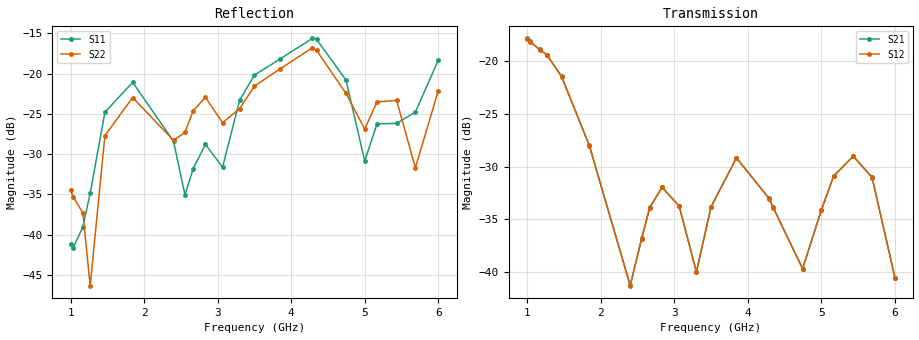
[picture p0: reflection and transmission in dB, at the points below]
!Agilent Technologies,E8364B,MY43040528,A.07.50.67
!Agilent E8364B: A.07.50.67
!Date: Sunday, March 01, 2026 21:28:26
!Correction: S11(Full 2 Port(1,2))
!S21(Full 2 Port(1,2))
!S12(Full 2 Port(1,2))
!S22(Full 2 Port(1,2))
!S2P File: Measurements: S11, S21, S12, S22:
# Hz S  dB  R 50
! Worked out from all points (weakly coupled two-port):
!   451 points, 1 GHz to 6 GHz, reference 50 ohm
!   highest |S21| = -17.90 dB at 1 GHz (marker M1); lowest = -41.2 dB at 2.4 GHz (marker M2)
!   lowest |S11| = -41.7 dB at 1.033 GHz (marker M3), VSWR 1.02, Z = 49.9 + j0.809 ohm
!   |S11| at or under -10 dB: start of sweep to end of sweep
!   |S22| runs from -46.3 to -16.7 dB; largest |S21 - S12| = 0.00049
!   S11 on the Smith chart (normalised r, x): 1 GHz: 1.00, +0.02; 4.289 GHz: 1.25, -0.28; 6 GHz: 0.98, -0.24
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1e9  -41.15 78.0  -17.90 25.8  -17.94 25.8  -34.42 14.5
1.033333e9  -41.71 99.3  -18.16 15.9  -18.20 15.9  -35.28 15.4
1.166667e9  -39.04 139.5  -18.93 -24.2  -18.96 -24.2  -37.28 15.5
1.266667e9  -34.86 170.4  -19.44 -56.7  -19.47 -56.7  -46.34 67.7
1.466667e9  -24.79 155.2  -21.49 -125.0  -21.51 -125.0  -27.70 86.2
1.844444e9  -21.07 87.2  -28.01 114.5  -28.04 114.5  -22.96 -1.4
2.4e9  -28.40 15.2  -41.22 -129.7  -41.25 -129.7  -28.28 -63.2
2.555556e9  -35.07 39.8  -36.78 117.8  -36.82 117.8  -27.29 -50.3
2.666667e9  -31.81 69.5  -33.84 62.1  -33.87 62.2  -24.61 -57.5
2.833333e9  -28.78 56.5  -31.94 -10.3  -31.97 -10.2  -22.93 -86.5
3.066667e9  -31.62 70.2  -33.74 -100.3  -33.77 -100.3  -26.10 -114.1
3.3e9  -23.26 79.1  -39.93 -136.5  -39.97 -136.5  -24.33 -100.2
3.5e9  -20.18 50.5  -33.78 -159.6  -33.82 -159.5  -21.54 -124.1
3.844444e9  -18.19 18.9  -29.17 73.7  -29.20 73.7  -19.43 -155.4
4.288889e9  -15.61 -41.8  -33.00 -91.7  -33.04 -91.6  -16.77 125.0
4.344444e9  -15.72 -50.4  -33.85 -111.7  -33.89 -111.7  -17.09 113.9
4.744444e9  -20.78 -110.1  -39.63 56.3  -39.67 56.3  -22.44 38.0
5e9  -30.86 -94.3  -34.08 -95.3  -34.11 -95.3  -26.87 39.2
5.166667e9  -26.22 -66.4  -30.88 -174.0  -30.92 -173.9  -23.50 27.9
5.433333e9  -26.18 -92.0  -29.01 68.7  -29.04 68.7  -23.32 -30.2
5.688889e9  -24.76 -55.8  -31.01 -40.2  -31.05 -40.2  -31.70 -28.9
6e9  -18.33 -88.4  -40.48 -151.6  -40.51 -151.6  -22.10 -27.2
